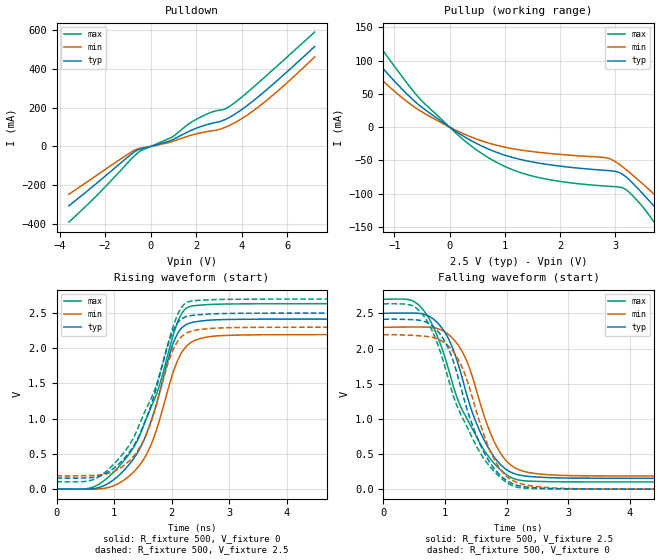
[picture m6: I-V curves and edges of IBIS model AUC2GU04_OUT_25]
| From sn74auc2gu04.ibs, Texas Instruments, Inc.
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[Model]   AUC2GU04_OUT_25
Model_type  Output
Vref =   0
Rref =   500
Cref =   30p
Vmeas =   1.25
| variable   typ   min   max
C_comp   4.21pF   3.26pF   4.93pF
| C_pullup   4.35pF   3.26pF   4.93pF
| C_pulldown   4.08pF   3.72pF   4.53pF
[Temperature Range]   40   100   -40
| Ambient temperature   25   85   -40
[Voltage range]   2.5   2.3   2.7
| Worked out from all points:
|   slope of the pulldown table from 0 to 0.375 V, typ, clamps not added: 31 ohm
|   slope of the pullup table from 0 to 0.375 V, typ, clamps not added: 19.2 ohm
|   rising waveform, R_fixture 500, V_fixture 0: 20-80 % time 590ps typ, 542ps min, 712ps max; typ from 0 V to 2.42 V
|   falling waveform, R_fixture 500, V_fixture 2.5: 20-80 % time 568ps typ, 511ps min, 716ps max; typ from 2.5 V to 0.154 V
|   rising waveform, R_fixture 500, V_fixture 2.5: 20-80 % time 581ps typ, 518ps min, 715ps max; typ from 0.154 V to 2.5 V
|   falling waveform, R_fixture 500, V_fixture 0: 20-80 % time 571ps typ, 526ps min, 704ps max; typ from 2.42 V to 0 V
[Pulldown]
| AUC2GU04_OUT_25
|   Voltage   I(typ)   I(min)   I(max)
-3.6V     -306.7mA   -247.2mA   -391.4mA
-2.415V   -194mA     -152.5mA   -258.9mA
-1.06V    -60.05mA   -44.48mA   -90.93mA
-495mV    -15.07mA   -10.2mA    -26.76mA
940mV     33.28mA    24.93mA    48.06mA
1.655V    76.17mA    53.44mA    114.5mA
2.135V    99.71mA    68.51mA    148.2mA
2.72V     120.3mA    81.01mA    178.7mA
3.27V     138.8mA    98.49mA    193.8mA
3.745V    170mA      125.4mA    230.6mA
5.185V    301.9mA    246.4mA    376.2mA
7.2V      515.3mA    461.9mA    590.3mA
[Pullup]
| AUC2GU04_OUT_25
|   Voltage   I(typ)   I(min)   I(max)
-3.6V     340.3mA    307.1mA    381.6mA
-2.205V   189.2mA    158.8mA    229mA
-1.83V    149.9mA    122.8mA    186.3mA
-1.595V   125.8mA    101.6mA    159.3mA
-570mV    34.24mA    26.44mA    45.37mA
555mV     -27.3mA    -19.82mA   -38.03mA
1.505V    -52.36mA   -36.76mA   -73.56mA
3.05V     -67.49mA   -54.38mA   -89.69mA
3.825V    -129.7mA   -109.6mA   -156.2mA
4.14V     -159.1mA   -133.8mA   -192.1mA
4.34V     -177.9mA   -149.3mA   -214.8mA
7.2V      -444.7mA   -374.8mA   -531.8mA
[Ramp]
| AUC2GU04_OUT_25
| variable   typ   min   max
dV/dt_r   1.45/5.96E-10   1.32/5.48E-10   1.58/7.14E-10
dV/dt_f   1.41/5.74E-10   1.27/5.16E-10   1.56/7.19E-10
R_load = 500
[Rising Waveform]
| AUC2GU04_OUT_25
R_fixture =   500
C_fixture =   0
L_fixture =   0
V_fixture =   0
V_fixture_min = 0
V_fixture_max = 0
|   Time   V(typ)   V(min)   V(max)
0s        5.929nV    18.6nV     437.6pV
715ps     14.61mV    -1.632mV   56.61mV
1.035ns   156.6mV    58.7mV     273.4mV
1.37ns    466mV      265.8mV    632.1mV
1.675ns   1.04V      694mV      1.221V
2.055ns   2.125V     1.723V     2.254V
2.2ns     2.307V     1.969V     2.522V
2.37ns    2.37V      2.099V     2.604V
3.66ns    2.414V     2.193V     2.633V
22ns      2.416V     2.195V     2.634V
[Falling Waveform]
| AUC2GU04_OUT_25
R_fixture =   500
C_fixture =   0
L_fixture =   0
V_fixture =   2.5
V_fixture_min = 2.3
V_fixture_max = 2.7
|   Time   V(typ)   V(min)   V(max)
0s        2.5V       2.3V       2.7V
445ps     2.504V     2.305V     2.688V
640ps     2.491V     2.305V     2.556V
890ps     2.354V     2.279V     2.145V
1.12ns    2.015V     2.148V     1.511V
1.36ns    1.324V     1.809V     994.9mV
1.675ns   632.4mV    941.6mV    503mV
1.945ns   314.1mV    457.1mV    241.6mV
2.25ns    193.7mV    260.9mV    122.6mV
22ns      154.5mV    186.3mV    102.6mV
[Rising Waveform]
| AUC2GU04_OUT_25
R_fixture =   500
C_fixture =   0
L_fixture =   0
V_fixture =   2.5
V_fixture_min = 2.3
V_fixture_max = 2.7
|   Time   V(typ)   V(min)   V(max)
0s        154.5mV    186.3mV    102.6mV
700ps     172.6mV    194.4mV    155.1mV
1.005ns   300.2mV    252mV      360.3mV
1.3ns     559.1mV    427.9mV    670.2mV
1.61ns    1.11V      876.6mV    1.224V
1.75ns    1.48V      1.236V     1.512V
2.025ns   2.245V     1.976V     2.303V
2.18ns    2.421V     2.17V      2.589V
2.36ns    2.468V     2.247V     2.675V
22ns      2.5V       2.3V       2.7V
[Falling Waveform]
| AUC2GU04_OUT_25
R_fixture =   500
C_fixture =   0
L_fixture =   0
V_fixture =   0
V_fixture_min = 0
V_fixture_max = 0
|   Time   V(typ)   V(min)   V(max)
0s        2.416V     2.195V     2.634V
440ps     2.411V     2.188V     2.618V
625ps     2.394V     2.178V     2.495V
850ps     2.278V     2.146V     2.131V
1.08ns    1.95V      2.013V     1.49V
1.32ns    1.247V     1.642V     953.9mV
1.65ns    496.8mV    729.9mV    411.1mV
1.92ns    178.3mV    259.4mV    150.5mV
2.235ns   41.85mV    75.47mV    19.11mV
22ns      -90.19nV   -108.1nV   -49.36nV
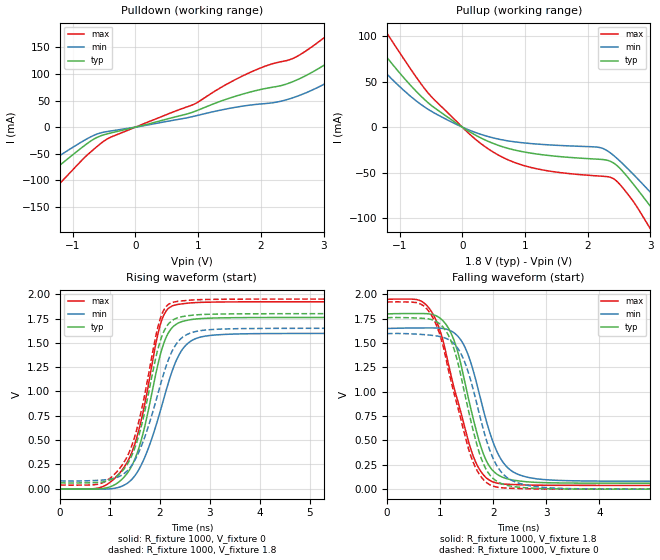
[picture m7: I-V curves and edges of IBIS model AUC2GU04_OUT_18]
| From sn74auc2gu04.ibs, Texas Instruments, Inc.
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[Model]   AUC2GU04_OUT_18
Model_type  Output
Vref =   0
Rref =   1000
Cref =   30p
Vmeas =   0.9
| variable   typ   min   max
C_comp   4.42pF   3.39pF   5.08pF
| C_pullup   4.56pF   3.39pF   5.08pF
| C_pulldown   4.28pF   4.06pF   4.76pF
[Temperature Range]   40   100   -40
| Ambient temperature   25   85   -40
[Voltage range]   1.8   1.65   1.95
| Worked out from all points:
|   slope of the pulldown table from 0 to 0.27 V, typ, clamps not added: 34.3 ohm
|   slope of the pullup table from 0 to 0.27 V, typ, clamps not added: 24.6 ohm
|   rising waveform, R_fixture 1000, V_fixture 0: 20-80 % time 491ps typ, 602ps min, 493ps max; typ from 0 V to 1.76 V
|   falling waveform, R_fixture 1000, V_fixture 1.8: 20-80 % time 476ps typ, 507ps min, 540ps max; typ from 1.8 V to 0.061 V
|   rising waveform, R_fixture 1000, V_fixture 1.8: 20-80 % time 480ps typ, 585ps min, 497ps max; typ from 0.061 V to 1.8 V
|   falling waveform, R_fixture 1000, V_fixture 0: 20-80 % time 473ps typ, 514ps min, 530ps max; typ from 1.76 V to 0 V
[Pulldown]
| AUC2GU04_OUT_18
|   Voltage   I(typ)   I(min)   I(max)
-3.6V     -296.4mA   -240mA     -375.7mA
-3.04V    -245.1mA   -196.3mA   -315mA
-2.6V     -204.4mA   -162mA     -267mA
-2.255V   -172.2mA   -135mA     -229mA
-1.885V   -137.1mA   -106mA     -187.3mA
-775mV    -31.34mA   -22.15mA   -53.07mA
-465mV    -13.08mA   -8.59mA    -23.31mA
2.315V    77.77mA    48.55mA    122.7mA
3.28V     137.6mA    98.57mA    193.6mA
3.84V     187.3mA    142.5mA    250.2mA
4.36V     237.8mA    189.3mA    304.4mA
7.2V      540mA      495.6mA    606.6mA
[Pullup]
| AUC2GU04_OUT_18
|   Voltage   I(typ)   I(min)   I(max)
-3.6V     317.7mA    284.6mA    357mA
-1.845V   136.6mA    109.5mA    172.5mA
-1.56V    109.2mA    85.56mA    141.8mA
-1.29V    84.39mA    64.66mA    112.7mA
-545mV    26.78mA    19.58mA    37.49mA
330mV     -13mA      -8.667mA   -19.82mA
1.025V    -27.77mA   -17.59mA   -43.06mA
2.405V    -39.11mA   -30.66mA   -56.38mA
3.01V     -87.9mA    -72.3mA    -112.9mA
3.235V    -108.6mA   -89.1mA    -138.6mA
3.495V    -132.7mA   -108.9mA   -168.1mA
7.2V      -476mA     -398.9mA   -577.2mA
[Ramp]
| AUC2GU04_OUT_18
| variable   typ   min   max
dV/dt_r   1.06/4.94E-10   0.96/6.08E-10   1.15/4.98E-10
dV/dt_f   1.05/4.83E-10   0.95/5.16E-10   1.15/5.45E-10
R_load = 1000
[Rising Waveform]
| AUC2GU04_OUT_18
R_fixture =   1000
C_fixture =   0
L_fixture =   0
V_fixture =   0
V_fixture_min = 0
V_fixture_max = 0
|   Time   V(typ)   V(min)   V(max)
0s        4.682nV    17.04nV    293.6pV
845ps     1.822mV    -3.823mV   20.04mV
1.345ns   159.4mV    56.36mV    274.2mV
1.625ns   499.6mV    244mV      704.5mV
2.025ns   1.411V     830.7mV    1.717V
2.175ns   1.607V     1.098V     1.857V
2.365ns   1.703V     1.359V     1.895V
2.725ns   1.745V     1.545V     1.914V
3.59ns    1.759V     1.592V     1.921V
22.2ns    1.761V     1.597V     1.922V
[Falling Waveform]
| AUC2GU04_OUT_18
R_fixture =   1000
C_fixture =   0
L_fixture =   0
V_fixture =   1.8
V_fixture_min = 1.65
V_fixture_max = 1.95
|   Time   V(typ)   V(min)   V(max)
0s        1.8V       1.65V      1.95V
735ps     1.803V     1.656V     1.894V
1.125ns   1.681V     1.642V     1.362V
1.425ns   1.199V     1.502V     716.5mV
1.645ns   676.8mV    1.175V     309.5mV
1.86ns    303.4mV    720mV      121mV
2.095ns   144.9mV    357.9mV    59.95mV
2.48ns    84.98mV    149.1mV    45.91mV
3.4ns     63.05mV    87.23mV    39.22mV
22.2ns    61.05mV    81.2mV     38.68mV
[Rising Waveform]
| AUC2GU04_OUT_18
R_fixture =   1000
C_fixture =   0
L_fixture =   0
V_fixture =   1.8
V_fixture_min = 1.65
V_fixture_max = 1.95
|   Time   V(typ)   V(min)   V(max)
0s        61.05mV    81.2mV     38.68mV
820ps     67.95mV    88.68mV    56.19mV
1.265ns   193.9mV    150.1mV    260.8mV
1.58ns    552.5mV    380mV      698.6mV
2.015ns   1.533V     1.079V     1.762V
2.15ns    1.681V     1.299V     1.887V
2.345ns   1.756V     1.5V       1.926V
2.72ns    1.787V     1.617V     1.943V
3.62ns    1.798V     1.646V     1.949V
22.2ns    1.8V       1.65V      1.95V
[Falling Waveform]
| AUC2GU04_OUT_18
R_fixture =   1000
C_fixture =   0
L_fixture =   0
V_fixture =   0
V_fixture_min = 0
V_fixture_max = 0
|   Time   V(typ)   V(min)   V(max)
0s        1.761V     1.597V     1.922V
725ps     1.752V     1.586V     1.865V
1.105ns   1.627V     1.55V      1.353V
1.38ns    1.192V     1.404V     740.4mV
1.62ns    607.3mV    1.029V     279.8mV
1.835ns   236.2mV    571.3mV    86.7mV
2.085ns   75.35mV    225.7mV    19.42mV
2.49ns    20.22mV    59.89mV    6.576mV
3.495ns   1.506mV    5.078mV    424.6uV
22.2ns    -115.5nV   -146.3nV   -46.9nV
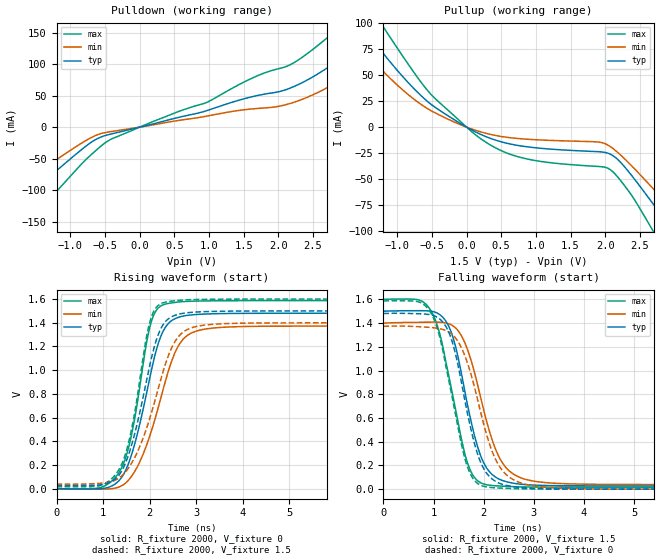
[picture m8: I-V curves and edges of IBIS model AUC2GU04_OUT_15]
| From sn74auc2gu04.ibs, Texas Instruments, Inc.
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[Model]   AUC2GU04_OUT_15
Model_type  Output
Vref =   0
Rref =   2000
Cref =   15p
Vmeas =   0.75
| variable   typ   min   max
C_comp   4.54pF   3.49pF   5.16pF
| C_pullup   4.65pF   3.49pF   5.16pF
| C_pulldown   4.43pF   4.17pF   4.80pF
[Temperature Range]   40   100   -40
| Ambient temperature   25   85   -40
[Voltage range]   1.5   1.4   1.6
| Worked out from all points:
|   slope of the pulldown table from 0 to 0.225 V, typ, clamps not added: 37.2 ohm
|   slope of the pullup table from 0 to 0.225 V, typ, clamps not added: 29.5 ohm
|   rising waveform, R_fixture 2000, V_fixture 0: 20-80 % time 536ps typ, 652ps min, 425ps max; typ from 0 V to 1.48 V
|   falling waveform, R_fixture 2000, V_fixture 1.5: 20-80 % time 469ps typ, 545ps min, 464ps max; typ from 1.5 V to 0.027 V
|   rising waveform, R_fixture 2000, V_fixture 1.5: 20-80 % time 529ps typ, 670ps min, 423ps max; typ from 0.027 V to 1.5 V
|   falling waveform, R_fixture 2000, V_fixture 0: 20-80 % time 467ps typ, 563ps min, 459ps max; typ from 1.48 V to 0 V
[Pulldown]
| AUC2GU04_OUT_15
|   Voltage   I(typ)   I(min)   I(max)
-3.6V     -291.8mA   -237mA     -368.2mA
-2.58V    -198.3mA   -157.7mA   -257.6mA
-2.195V   -162.8mA   -127.9mA   -215.5mA
-1.66V    -112.8mA   -86.57mA   -156mA
-780mV    -30.56mA   -21.54mA   -51.92mA
-475mV    -12.67mA   -8.191mA   -23.15mA
1.705V    50.42mA    29.75mA    81.93mA
2.175V    62.26mA    37.78mA    99.39mA
2.875V    107mA      73.24mA    158.1mA
3.46V     157.5mA    116.6mA    216.9mA
3.985V    207.9mA    162.5mA    271.6mA
7.2V      550.1mA    508.9mA    613.8mA
[Pullup]
| AUC2GU04_OUT_15
|   Voltage   I(typ)   I(min)   I(max)
-3.6V     307.3mA    275.5mA    344.5mA
-1.765V   121.5mA    96.49mA    155.1mA
-1.505V   97.43mA    75.63mA    128mA
-1.255V   75.46mA    57.26mA    102.1mA
-555mV    24.23mA    17.49mA    34.66mA
170mV     -5.955mA   -3.89mA    -9.475mA
850mV     -18.72mA   -11.52mA   -30.31mA
2.035V    -25.01mA   -17.16mA   -39.48mA
2.67V     -72.04mA   -57.7mA    -97.61mA
2.91V     -93.92mA   -75.38mA   -124.9mA
3.185V    -119.3mA   -96.09mA   -155.9mA
7.2V      -490.1mA   -409.4mA   -598.1mA
[Ramp]
| AUC2GU04_OUT_15
| variable   typ   min   max
dV/dt_r   0.89/5.42E-10   0.83/6.57E-10   0.95/4.30E-10
dV/dt_f   0.89/4.72E-10   0.82/5.53E-10   0.95/4.66E-10
R_load = 2000
[Rising Waveform]
| AUC2GU04_OUT_15
R_fixture =   2000
C_fixture =   0
L_fixture =   0
V_fixture =   0
V_fixture_min = 0
V_fixture_max = 0
|   Time   V(typ)   V(min)   V(max)
0s        4.321nV    17.19nV    241pV
945ps     -462.2uV   -4.552mV   9.192mV
1.345ns   68.28mV    14.05mV    137.7mV
1.61ns    284.1mV    103mV      450.7mV
2.035ns   991.2mV    482.4mV    1.407V
2.23ns    1.274V     748.4mV    1.538V
2.435ns   1.406V     1.031V     1.565V
2.83ns    1.463V     1.298V     1.581V
3.725ns   1.478V     1.365V     1.586V
23.3ns    1.481V     1.373V     1.587V
[Falling Waveform]
| AUC2GU04_OUT_15
R_fixture =   2000
C_fixture =   0
L_fixture =   0
V_fixture =   1.5
V_fixture_min = 1.4
V_fixture_max = 1.6
|   Time   V(typ)   V(min)   V(max)
0s        1.5V       1.4V       1.6V
850ps     1.504V     1.407V     1.558V
1.055ns   1.488V     1.408V     1.404V
1.24ns    1.42V      1.401V     1.085V
1.435ns   1.208V     1.361V     679.9mV
1.68ns    705.1mV    1.173V     217.5mV
2.08ns    165.3mV    538.3mV    35.64mV
2.51ns    57.07mV    153.5mV    22.97mV
3.425ns   29.79mV    49.61mV    16.93mV
23.3ns    27.17mV    38.78mV    16.4mV
[Rising Waveform]
| AUC2GU04_OUT_15
R_fixture =   2000
C_fixture =   0
L_fixture =   0
V_fixture =   1.5
V_fixture_min = 1.4
V_fixture_max = 1.6
|   Time   V(typ)   V(min)   V(max)
0s        27.17mV    38.78mV    16.4mV
945ps     32.3mV     45.47mV    27.27mV
1.335ns   110.6mV    87.55mV    155.8mV
1.6ns     349.9mV    206mV      477.8mV
2.015ns   1.06V      607.9mV    1.419V
2.19ns    1.304V     849.1mV    1.548V
2.375ns   1.424V     1.091V     1.577V
2.775ns   1.483V     1.335V     1.593V
3.645ns   1.498V     1.393V     1.599V
23.3ns    1.5V       1.4V       1.6V
[Falling Waveform]
| AUC2GU04_OUT_15
R_fixture =   2000
C_fixture =   0
L_fixture =   0
V_fixture =   0
V_fixture_min = 0
V_fixture_max = 0
|   Time   V(typ)   V(min)   V(max)
0s        1.481V     1.373V     1.587V
850ps     1.475V     1.366V     1.54V
1.05ns    1.455V     1.358V     1.386V
1.235ns   1.379V     1.339V     1.059V
1.42ns    1.169V     1.283V     668.4mV
1.665ns   661.2mV    1.078V     201.4mV
2.07ns    127.8mV    442.2mV    17.96mV
2.495ns   27.92mV    106mV      6.482mV
3.465ns   2.225mV    9.481mV    470.8uV
23.3ns    -150nV     -189nV     -22.52nV
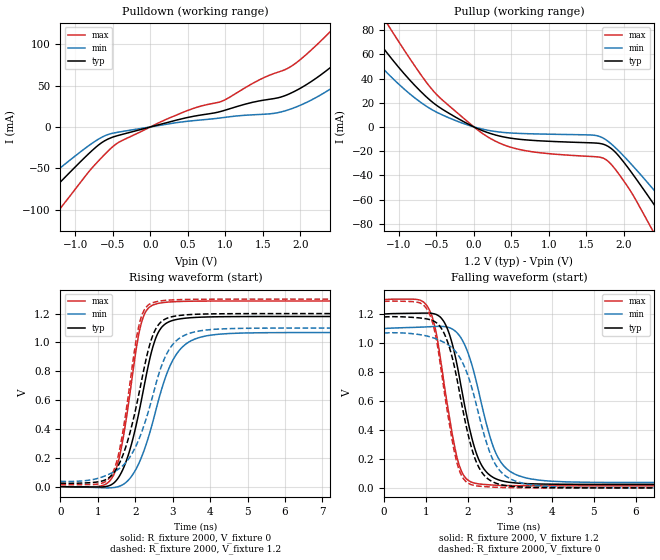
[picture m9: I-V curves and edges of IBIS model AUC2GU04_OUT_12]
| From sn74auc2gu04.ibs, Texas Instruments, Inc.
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[Model]   AUC2GU04_OUT_12
Model_type  Output
Vref =   0
Rref =   2000
Cref =   15p
Vmeas =   0.6
| variable   typ   min   max
C_comp   4.64pF   3.58pF   5.25pF
| C_pullup   4.72pF   3.58pF   5.25pF
| C_pulldown   4.57pF   4.23pF   4.91pF
[Temperature Range]   40   100   -40
| Ambient temperature   25   85   -40
[Voltage range]   1.2   1.1   1.3
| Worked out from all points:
|   slope of the pulldown table from 0 to 0.18 V, typ, clamps not added: 42.1 ohm
|   slope of the pullup table from 0 to 0.18 V, typ, clamps not added: 39.1 ohm
|   rising waveform, R_fixture 2000, V_fixture 0: 20-80 % time 610ps typ, 780ps min, 456ps max; typ from 0 V to 1.18 V
|   falling waveform, R_fixture 2000, V_fixture 1.2: 20-80 % time 525ps typ, 598ps min, 432ps max; typ from 1.2 V to 0.024 V
|   rising waveform, R_fixture 2000, V_fixture 1.2: 20-80 % time 640ps typ, 824ps min, 450ps max; typ from 0.024 V to 1.2 V
|   falling waveform, R_fixture 2000, V_fixture 0: 20-80 % time 544ps typ, 678ps min, 428ps max; typ from 1.18 V to 0 V
[Pulldown]
| AUC2GU04_OUT_12
|   Voltage   I(typ)   I(min)   I(max)
-3.6V     -287.1mA   -233.4mA   -361.8mA
-2.265V   -164.9mA   -130mA     -217mA
-1.8V     -122.1mA   -94.37mA   -165.9mA
-1.435V   -88.34mA   -66.79mA   -125.2mA
-725mV    -24.34mA   -16.62mA   -44.29mA
-450mV    -10.86mA   -6.7mA     -20.27mA
965mV     19.4mA     11.26mA    31.48mA
1.83V     39.08mA    20.37mA    70.79mA
2.445V    74.97mA    48.4mA     119.6mA
3.035V    123.7mA    89.46mA    177.8mA
3.45V     162.3mA    124mA      220.7mA
7.2V      559.7mA    525.3mA    619.4mA
[Pullup]
| AUC2GU04_OUT_12
|   Voltage   I(typ)   I(min)   I(max)
-3.6V     296.6mA    264.5mA    333.4mA
-1.72V    109.3mA    85.03mA    141.9mA
-1.385V   79.69mA    59.83mA    108mA
-1.155V   60.82mA    44.47mA    85.17mA
-545mV    20.04mA    13.75mA    30mA
55mV      -1.563mA   -922.8uA   -2.727mA
610mV     -10.23mA   -5.378mA   -18.68mA
1.74V     -14.59mA   -9.768mA   -26.21mA
2.39V     -62.88mA   -51.24mA   -86.14mA
2.645V    -86.04mA   -69.97mA   -115mA
2.945V    -113.6mA   -92.51mA   -148.7mA
7.2V      -505.1mA   -423.6mA   -616mA
[Ramp]
| AUC2GU04_OUT_12
| variable   typ   min   max
dV/dt_r   0.71/6.16E-10   0.65/7.90E-10   0.77/4.61E-10
dV/dt_f   0.71/5.33E-10   0.65/6.09E-10   0.77/4.38E-10
R_load = 2000
[Rising Waveform]
| AUC2GU04_OUT_12
R_fixture =   2000
C_fixture =   0
L_fixture =   0
V_fixture =   0
V_fixture_min = 0
V_fixture_max = 0
|   Time   V(typ)   V(min)   V(max)
0s        4.067nV    18.31nV    200.9pV
1.065ns   -2.787mV   -7.505mV   3.212mV
1.415ns   22.47mV    -7.01mV    76.73mV
1.66ns    114mV      12.42mV    312.8mV
2.155ns   587.7mV    196.5mV    1.127V
2.41ns    910.2mV    393.4mV    1.25V
2.62ns    1.071V     598mV      1.271V
3.21ns    1.164V     954.6mV    1.284V
4.225ns   1.178V     1.056V     1.287V
22.7ns    1.18V      1.069V     1.287V
[Falling Waveform]
| AUC2GU04_OUT_12
R_fixture =   2000
C_fixture =   0
L_fixture =   0
V_fixture =   1.2
V_fixture_min = 1.1
V_fixture_max = 1.3
|   Time   V(typ)   V(min)   V(max)
0s        1.2V       1.1V       1.3V
1.02ns    1.206V     1.111V     1.258V
1.22ns    1.199V     1.114V     1.102V
1.42ns    1.151V     1.114V     743.8mV
1.785ns   783.1mV    1.055V     163.7mV
2.185ns   252.5mV    751.6mV    30.93mV
2.525ns   87.15mV    354mV      20.77mV
2.75ns    53.31mV    193.6mV    17.1mV
3.69ns    26.7mV     53.6mV     14.2mV
22.7ns    23.98mV    36.64mV    13.86mV
[Rising Waveform]
| AUC2GU04_OUT_12
R_fixture =   2000
C_fixture =   0
L_fixture =   0
V_fixture =   1.2
V_fixture_min = 1.1
V_fixture_max = 1.3
|   Time   V(typ)   V(min)   V(max)
0s        23.98mV    36.64mV    13.86mV
1.045ns   34.42mV    60.54mV    19.13mV
1.38ns    81.32mV    95.38mV    87.19mV
1.63ns    192.6mV    137.1mV    323.5mV
2.125ns   678.7mV    346.3mV    1.145V
2.375ns   973.5mV    543.4mV    1.265V
2.585ns   1.11V      742.6mV    1.283V
3.11ns    1.184V     1.014V     1.296V
4.11ns    1.198V     1.091V     1.3V
22.7ns    1.2V       1.1V       1.3V
[Falling Waveform]
| AUC2GU04_OUT_12
R_fixture =   2000
C_fixture =   0
L_fixture =   0
V_fixture =   0
V_fixture_min = 0
V_fixture_max = 0
|   Time   V(typ)   V(min)   V(max)
0s        1.18V      1.069V     1.287V
1.06ns    1.164V     1.045V     1.215V
1.235ns   1.143V     1.029V     1.044V
1.43ns    1.068V     1.004V     676.2mV
1.735ns   757.3mV    930.4mV    176.5mV
2.165ns   205.1mV    614.5mV    15.83mV
2.465ns   64.85mV    292.6mV    7.431mV
2.715ns   27.56mV    135.5mV    3.326mV
3.68ns    2.42mV     14.63mV    330.9uV
22.7ns    -180.3nV   -287.3nV   -54.52nV
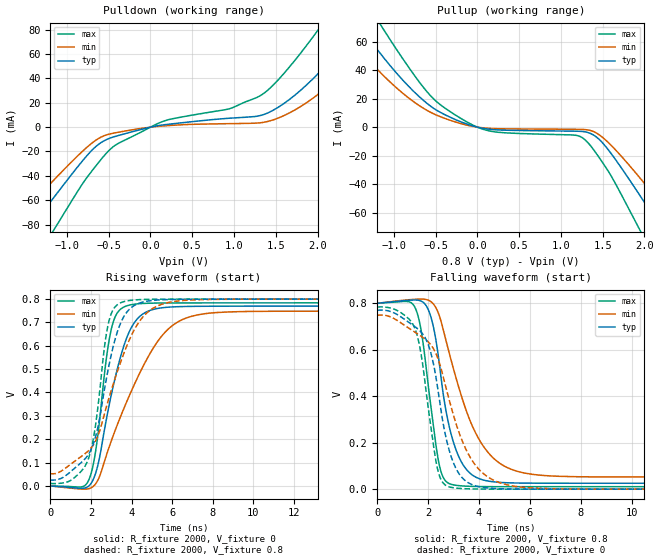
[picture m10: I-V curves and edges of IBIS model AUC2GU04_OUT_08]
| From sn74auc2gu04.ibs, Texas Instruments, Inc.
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[Model]   AUC2GU04_OUT_08
Model_type  Output
Vref =   0
Rref =   2000
Cref =   15p
Vmeas =   0.4
| variable   typ   min   max
C_comp   4.75pF   3.89pF   5.25pF
| C_pullup   4.71pF   3.89pF   5.25pF
| C_pulldown   4.78pF   4.42pF   5.16pF
[Temperature Range]   40   100   -40
| Ambient temperature   25   85   -40
[Voltage range]   0.8   0.8   0.8
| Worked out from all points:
|   slope of the pulldown table from 0 to 0.12 V, typ, clamps not added: 77 ohm
|   slope of the pullup table from 0 to 0.12 V, typ, clamps not added: 93.5 ohm
|   rising waveform, R_fixture 2000, V_fixture 0: 20-80 % time 1.19ns typ, 2.3ns min, 656ps max; typ from 0 V to 0.77 V
|   falling waveform, R_fixture 2000, V_fixture 0.8: 20-80 % time 758ps typ, 1.39ns min, 551ps max; typ from 0.8 V to 0.025 V
|   rising waveform, R_fixture 2000, V_fixture 0.8: 20-80 % time 1.13ns typ, 1.75ns min, 703ps max; typ from 0.025 V to 0.8 V
|   falling waveform, R_fixture 2000, V_fixture 0: 20-80 % time 839ps typ, 1.35ns min, 609ps max; typ from 0.77 V to 0 V
[Pulldown]
| AUC2GU04_OUT_08
|   Voltage   I(typ)   I(min)   I(max)
-3.6V     -280.8mA   -229.7mA   -351mA
-1.655V   -102.9mA   -80.11mA   -139.6mA
-1.49V    -87.89mA   -67.78mA   -121.4mA
-1.12V    -54.41mA   -40.75mA   -80.27mA
-695mV    -18.52mA   -12.78mA   -35.42mA
-450mV    -8.203mA   -5.055mA   -16.27mA
140mV     1.752mA    914.9uA    4.471mA
1.305V    9.359mA    3.511mA    25.45mA
2.03V     45.53mA    28.14mA    81.93mA
2.53V     85.16mA    59.72mA    131.1mA
2.825V    111.4mA    82.05mA    161.3mA
7.2V      570.6mA    542.7mA    625.4mA
[Pullup]
| AUC2GU04_OUT_08
|   Voltage   I(typ)   I(min)   I(max)
-3.6V     281.9mA    253.3mA    314.5mA
-1.635V   90.14mA    70.37mA    117.4mA
-1.4V     70.31mA    53.57mA    94.59mA
-1.18V    53.03mA    39.45mA    73.78mA
-570mV    15.15mA    10.71mA    22.62mA
-100mV    1.656mA    1.06mA     2.841mA
1.275V    -3.185mA   -1.669mA   -8.159mA
1.5V      -11.06mA   -7.216mA   -24.91mA
2.01V     -53.58mA   -40.09mA   -79.37mA
2.185V    -69.32mA   -52.69mA   -98.96mA
2.6V      -107.2mA   -83.48mA   -145.1mA
7.2V      -527.7mA   -440mA     -646.5mA
[Ramp]
| AUC2GU04_OUT_08
| variable   typ   min   max
dV/dt_r   0.47/1.20E-09   0.46/2.32E-09   0.47/6.66E-10
dV/dt_f   0.47/7.70E-10   0.46/1.40E-09   0.48/5.63E-10
R_load = 2000
[Rising Waveform]
| AUC2GU04_OUT_08
R_fixture =   2000
C_fixture =   0
L_fixture =   0
V_fixture =   0
V_fixture_min = 0
V_fixture_max = 0
|   Time   V(typ)   V(min)   V(max)
0s        5.047nV    30.02nV    159.4pV
1.91ns    734.9uV    -11.54mV   28.06mV
2.255ns   60.48mV    11.75mV    161.1mV
2.74ns    274.6mV    124.6mV    530.6mV
3ns       387.7mV    191.5mV    669.1mV
3.87ns    656.2mV    381.8mV    773.5mV
4.535ns   734.7mV    505.9mV    781mV
5.62ns    763.8mV    654.8mV    783.2mV
7.595ns   769.2mV    737.2mV    783.6mV
34.99ns   769.9mV    748.6mV    783.8mV
[Falling Waveform]
| AUC2GU04_OUT_08
R_fixture =   2000
C_fixture =   0
L_fixture =   0
V_fixture =   0.8
V_fixture_min = 0.8
V_fixture_max = 0.8
|   Time   V(typ)   V(min)   V(max)
0s        800mV      800mV      800mV
1.435ns   814.4mV    817.1mV    791.8mV
1.695ns   811.2mV    818.5mV    702mV
1.955ns   784.2mV    815.5mV    494.1mV
2.46ns    524.3mV    740.2mV    94.22mV
3ns       200.3mV    516.5mV    18.35mV
3.515ns   83.36mV    332.9mV    12.82mV
4.26ns    36.93mV    171.1mV    10.99mV
6.105ns   25.78mV    63.7mV     10.6mV
34.99ns   25.46mV    52.25mV    10.6mV
[Rising Waveform]
| AUC2GU04_OUT_08
R_fixture =   2000
C_fixture =   0
L_fixture =   0
V_fixture =   0.8
V_fixture_min = 0.8
V_fixture_max = 0.8
|   Time   V(typ)   V(min)   V(max)
0s        25.46mV    52.25mV    10.6mV
1.005ns   61.24mV    92.94mV    23.59mV
1.83ns    128.6mV    146.7mV    105.3mV
2.205ns   203.3mV    187.9mV    245.9mV
2.665ns   411.5mV    307.4mV    591.9mV
2.87ns    507.1mV    370.4mV    698.8mV
3.665ns   730.9mV    577mV      789.9mV
4.79ns    791.2mV    743.4mV    798.7mV
6.53ns    799mV      793.8mV    799.7mV
34.99ns   800mV      800mV      800mV
[Falling Waveform]
| AUC2GU04_OUT_08
R_fixture =   2000
C_fixture =   0
L_fixture =   0
V_fixture =   0
V_fixture_min = 0
V_fixture_max = 0
|   Time   V(typ)   V(min)   V(max)
0s        770mV      748.6mV    783.8mV
1.47ns    700.6mV    676.8mV    694.6mV
1.72ns    677.1mV    658.8mV    584.4mV
2.005ns   622.5mV    633.9mV    350.8mV
2.37ns    440.1mV    567.4mV    87.81mV
2.91ns    138.6mV    351.8mV    7.532mV
3.335ns   49.52mV    209mV      2.606mV
3.97ns    11.44mV    88.4mV     595.9uV
5.715ns   349.2uV    8.049mV    15.53uV
34.99ns   -171.2nV   -205.3nV   -88.5nV
